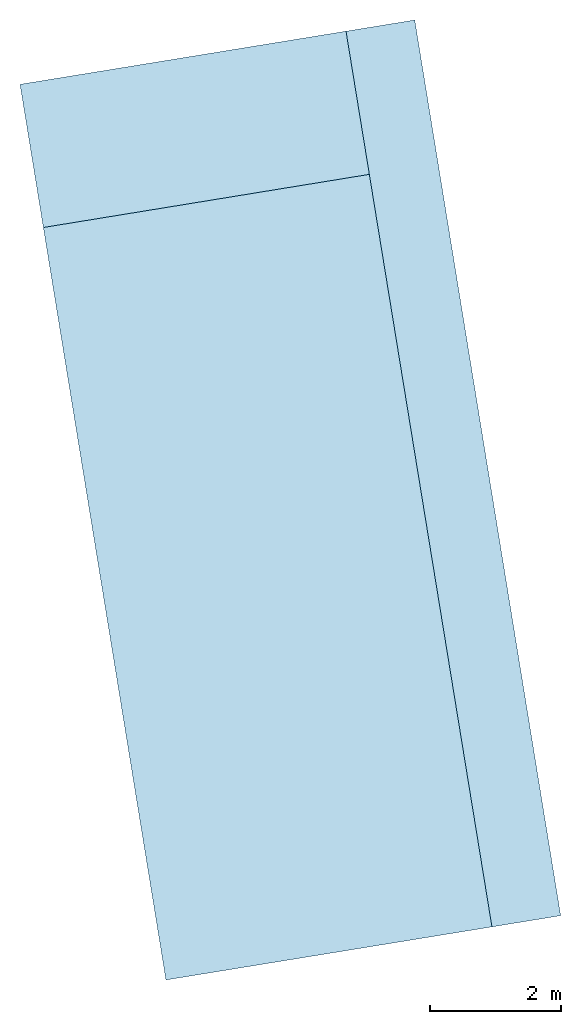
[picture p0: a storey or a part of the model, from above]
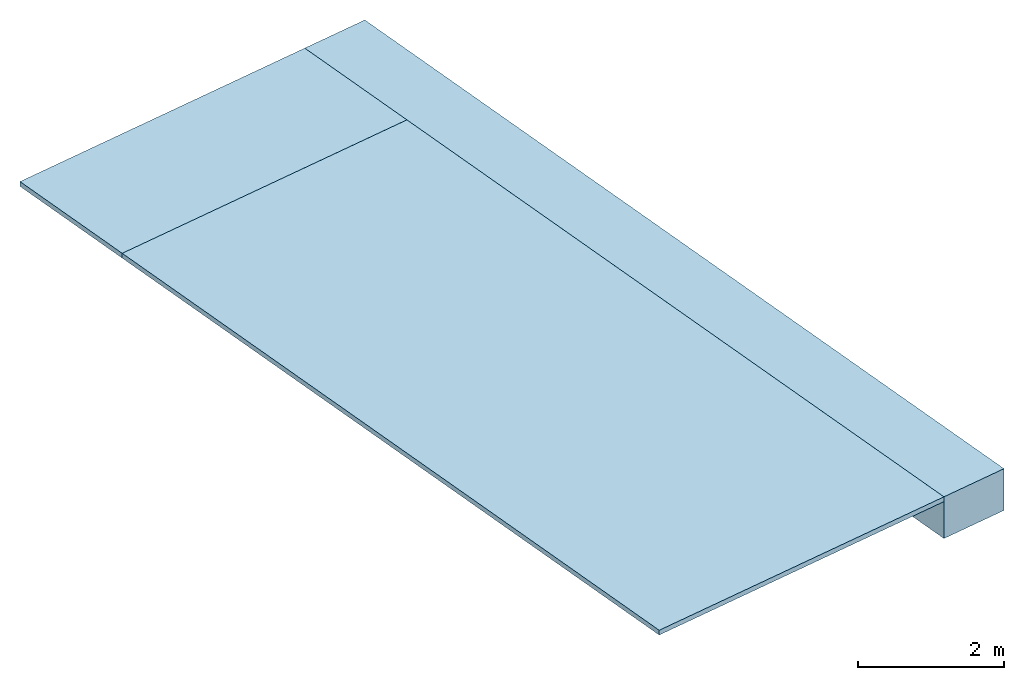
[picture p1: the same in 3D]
Properties of the parts of a building model (IFC2X3)

# File
Description: ViewDefinition [CoordinationView_V2.0]
File name: BR001-350-101.2.IFC (Edited by Naviate Simple BIM 2022 version 6)
Time: 2026-03-27T10:17:19+01:00
Written by: ODA SDAI 24.12
Made in: Autodesk Revit 25.4.41.14 (ENU) - IFC 25.4.0.27

# IfcProject, 01. Avinor Drift
LongName: Terminal 2 . Satellitt; Phase: Som Bygget

# IfcSite (2)
RefLatitude: 60, 17, 20, 899658; RefLongitude: 5, 13, 37, 654037; RefElevation: 0 mm

# IfcBuilding (2)
Name
br001-a-200-1-0001 | LongName: br001-a-200-1-0001


# IfcBuildingStorey: Level:Level - BR001_ARK, H01-Nivå D+0,36
In: br001-a-200-1-0001
LongName: H01-Nivå D+0,36; Elevation: 51360 mm

# IfcBuildingStorey: Level:NSW Kote - Triangel med navn og kote, Arial 2 mm KP, U01-Nivå B+3,1m
LongName: U01-Nivå B+3,1m; Elevation: 47800 mm

# IfcSlab: 700*13800, PLASSTØPTDEKKE
In: U01-Nivå B+3,1m
Type - PredefinedType: FLOOR
Description: 700*13800
ePset_SimplebimBasicQuantities - Area, top, net (Simplebim): 14.7961 m2; Thickness (Simplebim): 700.004 mm; Area, largest surface, net (Simplebim): 14.7962 m2; Perimeter (Simplebim): 29900 mm; Area, sides, net (Simplebim): 20.9302 m2; Volume, net (Simplebim): 10.3572 m3
Pset_SlabCommon - Reference: 700*13800
ePset_Simplebim - Assembly Level: Leaf
ePset_LocationTool - Splitting: RESULT

# IfcSlab: 80*12000 (2)
In: U01-Nivå B+3,1m
Type - PredefinedType: FLOOR
Description: 80*12000
Pset_SlabCommon - Reference: 80*12000
ePset_Simplebim - Assembly Level: Leaf
ePset_LocationTool - Splitting: RESULT
Name | Area, largest surface, net (Simplebim) (m2) | Area, top, net (Simplebim) (m2) | Perimeter (Simplebim) (mm) | Thickness (Simplebim) (mm) | Volume, net (Simplebim) (m3) | Area, sides, net (Simplebim) (m2)
GULVPÅGRUNN | 11.2166 | 11.2163 | 14545.8 | 80.0079 | 0.89731 | 1.16378
GULVPÅGRUNN | 58.9538 | 58.9538 | 33437.4 | 80.0016 | 4.71631 | 2.67504

# IfcSlab: Floor:B250 - Betong - 500 mm, Floor:B250 - Betong - 500 mm:6508551
In: H01-Nivå D+0,36
Type - PredefinedType: FLOOR; Material: _NSW Betong 500 mm
Pset_SlabCommon - Reference: Floor:B250 - Betong - 500 mm
ePset_LocationTool - Splitting: RESULT
ePset_SimplebimBasicQuantities - Area, largest surface, net (Simplebim): 84.9662 m2; Area, top, net (Simplebim): 84.9662 m2; Area, sides, net (Simplebim): 20.0042 m2; Volume, net (Simplebim): 42.4831 m3; Perimeter (Simplebim): 40008.3 mm; Thickness (Simplebim): 500 mm
ePset_Simplebim - Assembly Level: Leaf

# IfcSlab: Floor:Eksisterende terrazzoflis, Floor:Eksisterende terrazzoflis:13875910
In: H01-Nivå D+0,36
Type - PredefinedType: FLOOR; Material: A255 - Flis 10 mm
ePset_LocationTool - Splitting: RESULT
Pset_SlabCommon - Reference: Floor:Eksisterende terrazzoflis
ePset_SimplebimBasicQuantities - Area, sides, net (Simplebim): 0.400494 m2; Area, top, net (Simplebim): 84.966 m2; Perimeter (Simplebim): 40049.4 mm; Volume, net (Simplebim): 0.849662 m3; Thickness (Simplebim): 10 mm; Area, largest surface, net (Simplebim): 84.9662 m2
ePset_Simplebim - Assembly Level: Leaf
